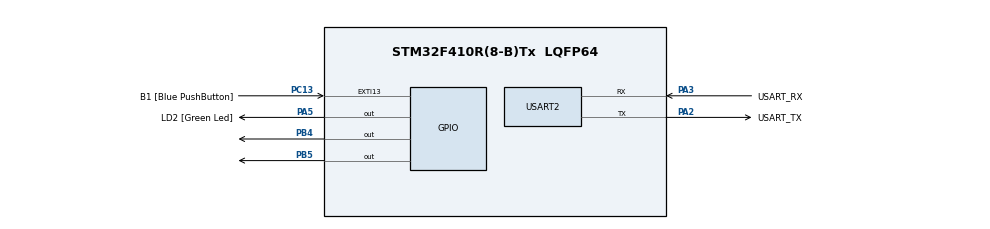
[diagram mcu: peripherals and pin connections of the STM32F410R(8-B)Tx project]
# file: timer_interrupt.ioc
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Dma.Request0=USART2_RX
Dma.Request1=USART2_TX
Dma.USART2_RX.0.Direction=DMA_PERIPH_TO_MEMORY
Dma.USART2_RX.0.FIFOMode=DMA_FIFOMODE_DISABLE
Dma.USART2_RX.0.Instance=DMA1_Stream5
Dma.USART2_RX.0.MemDataAlignment=DMA_MDATAALIGN_BYTE
Dma.USART2_RX.0.MemInc=DMA_MINC_ENABLE
Dma.USART2_RX.0.Mode=DMA_NORMAL
Dma.USART2_RX.0.PeriphDataAlignment=DMA_PDATAALIGN_BYTE
Dma.USART2_RX.0.PeriphInc=DMA_PINC_DISABLE
Dma.USART2_RX.0.Priority=DMA_PRIORITY_HIGH
Dma.USART2_TX.1.Direction=DMA_MEMORY_TO_PERIPH
Dma.USART2_TX.1.FIFOMode=DMA_FIFOMODE_DISABLE
Dma.USART2_TX.1.Instance=DMA1_Stream6
Dma.USART2_TX.1.MemDataAlignment=DMA_MDATAALIGN_BYTE
Dma.USART2_TX.1.MemInc=DMA_MINC_ENABLE
Dma.USART2_TX.1.Mode=DMA_NORMAL
Dma.USART2_TX.1.PeriphDataAlignment=DMA_PDATAALIGN_BYTE
Dma.USART2_TX.1.PeriphInc=DMA_PINC_DISABLE
Dma.USART2_TX.1.Priority=DMA_PRIORITY_HIGH
FREERTOS.Tasks01=defaultTask,0,128,StartDefaultTask,Default,NULL,Dynamic,NULL,NULL
FREERTOS.configUSE_NEWLIB_REENTRANT=1
Mcu.Family=STM32F4
Mcu.Name=STM32F410R(8-B)Tx
Mcu.Package=LQFP64
NVIC.DMA1_Stream5_IRQn=true\:5\:0\:false\:false\:true\:true\:false\:true\:true
NVIC.DMA1_Stream6_IRQn=true\:5\:0\:false\:false\:true\:true\:false\:true\:true
NVIC.PriorityGroup=NVIC_PRIORITYGROUP_4
NVIC.TIM1_BRK_TIM9_IRQn=true\:5\:0\:true\:false\:true\:true\:false\:true\:true
NVIC.TIM1_UP_IRQn=true\:5\:0\:false\:false\:true\:true\:true\:true\:true
NVIC.TimeBase=TIM1_BRK_TIM9_IRQn
NVIC.TimeBaseIP=TIM9
NVIC.USART2_IRQn=true\:5\:0\:false\:false\:true\:true\:true\:true\:true
PA13.GPIO_Label=TMS
PA13.Mode=Serial_Wire
PA13.Signal=SYS_JTMS-SWDIO
PA14.GPIO_Label=TCK
PA14.Mode=Serial_Wire
PA14.Signal=SYS_JTCK-SWCLK
PA2.GPIO_Label=USART_TX
PA2.Mode=Asynchronous
PA2.Signal=USART2_TX
PA3.GPIO_Label=USART_RX
PA3.Mode=Asynchronous
PA3.Signal=USART2_RX
PA5.GPIO_Label=LD2 [Green Led]
PA5.Signal=GPIO_Output
PB3.GPIO_Label=SWO
PB3.Signal=SYS_JTDO-SWO
PB4.Signal=GPIO_Output
PB5.Signal=GPIO_Output
PC13-ANTI_TAMP.GPIO_Label=B1 [Blue PushButton]
PC13-ANTI_TAMP.GPIO_ModeDefaultEXTI=GPIO_MODE_IT_FALLING
PC13-ANTI_TAMP.Signal=GPXTI13
PC14-OSC32_IN.Mode=LSE-External-Oscillator
PC14-OSC32_IN.Signal=RCC_OSC32_IN
PC15-OSC32_OUT.Mode=LSE-External-Oscillator
PC15-OSC32_OUT.Signal=RCC_OSC32_OUT
PH0\ -\ OSC_IN.Mode=HSE-External-Clock-Source
PH0\ -\ OSC_IN.Signal=RCC_OSC_IN
PH1\ -\ OSC_OUT.Mode=HSE-External-Clock-Source
PH1\ -\ OSC_OUT.Signal=RCC_OSC_OUT
ProjectManager.HeapSize=0x200
ProjectManager.StackSize=0x400
ProjectManager.TargetToolchain=STM32CubeIDE
RCC.48MHZClocksFreq_Value=84000000
RCC.AHBFreq_Value=84000000
RCC.APB1CLKDivider=RCC_HCLK_DIV2
RCC.APB1Freq_Value=42000000
RCC.APB1TimFreq_Value=84000000
RCC.APB2Freq_Value=84000000
RCC.APB2TimFreq_Value=84000000
RCC.CortexFreq_Value=84000000
RCC.FLatency-AdvancedSettings=FLASH_LATENCY_2
RCC.HCLKFreq_Value=84000000
RCC.HSE_VALUE=8000000
RCC.HSI_VALUE=16000000
RCC.PLLN=336
RCC.PLLP=RCC_PLLP_DIV4
RCC.SYSCLKFreq_VALUE=84000000
RCC.SYSCLKSource=RCC_SYSCLKSOURCE_PLLCLK
RCC.VCOOutputFreq_Value=336000000
USART2.VirtualMode=VM_ASYNC
VP_FATFS_VS_Generic.Mode=User_defined
VP_FREERTOS_VS_CMSIS_V1.Mode=CMSIS_V1
VP_SYS_VS_tim9.Mode=TIM9
VP_TIM1_VS_ClockSourceINT.Mode=Internal
board=NUCLEO-F410RB

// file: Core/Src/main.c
/* USER CODE BEGIN Header */
/**
  ******************************************************************************
  * @file           : main.c
  * @brief          : Main program body
  ******************************************************************************
  * @attention
  *
  * Copyright (c) 2024 STMicroelectronics.
  * All rights reserved.
  *
  * This software is licensed under terms that can be found in the LICENSE file
  * in the root directory of this software component.
  * If no LICENSE file comes with this software, it is provided AS-IS.
  *
  ******************************************************************************
  */
/* USER CODE END Header */
#include "main.h"
#include "string.h"
#include "freeRTOS.h"
#include "task.h"
#include <semphr.h>
#include <SEGGER_SYSVIEW.h>
#include <stm32f4xx_hal.h>
#include <stm32f4xx_it.h>
#include "fatfs.h"
#include "usart.h"
#include <timer.h>

/* USER CODE BEGIN Includes */

#define STACK_SIZE 128
void GreenTaskA( void * argument);
void BlueTaskB( void* argument );
void UartTaskC( void* argument );
void vHandlingTaskTimer (void* argument);
/* USER CODE END Includes */

/* USER CODE BEGIN PTD */
// Create storage for a pointer to a semaphore

SemaphoreHandle_t semPtr = NULL;

/* USER CODE END PTD */

TIM_HandleTypeDef htim1;

osThreadId defaultTaskHandle;

void SystemClock_Config(void);
static void MX_GPIO_Init(void);
static void MX_DMA_Init(void);
void MX_USART2_UART_Init(void);
static void MX_TIM1_Init(void);

int main(void)
{
  /* USER CODE BEGIN 1 */
	BaseType_t status;
  /* USER CODE END 1 */

  /* MCU Configuration--------------------------------------------------------*/

  /* Reset of all peripherals, Initializes the Flash interface and the Systick. */
  HAL_Init();

  /* Configure the system clock */
  SystemClock_Config();

  /* Initialize all configured peripherals */
  MX_GPIO_Init();
  MX_DMA_Init();
  MX_USART2_UART_Init();
  MX_FATFS_Init();
  MX_TIM1_Init();
  init_struct_timers();
  /* USER CODE BEGIN 2 */

  /* Init scheduler */
    SEGGER_SYSVIEW_Conf();

     		HAL_NVIC_SetPriorityGrouping(NVIC_PRIORITYGROUP_4);	//ensure proper priority grouping for freeRTOS

     		// Create a semaphore using the FreeRTOS Heap
     		semPtr = xSemaphoreCreateBinary();
     	    // Ensure the pointer is valid (semaphore created successfully)
     		assert_param(semPtr != NULL);

     		// Create TaskA as a higher priority than TaskB.  In this example, this isn't strictly necessary since the tasks
     		// spend nearly all of their time blocked

     		status=xTaskCreate(GreenTaskA, "GreenTaskA", STACK_SIZE, NULL, tskIDLE_PRIORITY + 2, NULL);
     		assert_param(status == pdPASS);
     		//xTaskCreateStatic(GreenTaskA, "GreenTaskA", STACK_SIZE, NULL, tskIDLE_PRIORITY + 2, GreenTaskStack, &GreenTaskTCB);
     		// Using an assert to ensure proper task creation
     		//xTaskCreateStatic(BlueTaskB, "BlueTaskB", STACK_SIZE, NULL, tskIDLE_PRIORITY + 2, BlueTaskStack, &BlueTaskTCB);
     		status=xTaskCreate(BlueTaskB, "BlueTaskB", STACK_SIZE, NULL, tskIDLE_PRIORITY + 2, NULL);
     		assert_param( status == pdPASS);

     		status=xTaskCreate(UartTaskC, "UartTaskC", STACK_SIZE, NULL, tskIDLE_PRIORITY + 2, NULL);
     		assert_param( status == pdPASS);

     		status=xTaskCreate(vHandlingTaskTimer, "vHandlingTaskTimer", STACK_SIZE, NULL, tskIDLE_PRIORITY + 2, NULL);
     		     		assert_param( status == pdPASS);
     		// Start the scheduler - shouldn't return unless there's a problem

     		HAL_TIM_Base_Start_IT(&htim1);

     		vTaskStartScheduler();

     		// If you've wound up here, there is likely an issue with over-running the freeRTOS heap
     		while(1)
     		{
     		}

   }

   /**
    * GreenTaskA periodically 'gives' semaphorePtr
    * NOTES:
    * - This semaphore isn't "given" to any task specifically
    * - Giving the semaphore doesn't prevent GreenTaskA from continuing to run.
    * - Note the green LED continues to blink at all times
    */
   void GreenTaskA( void* argument )
   {
   	uint_fast8_t count = 0;
   	while(1)
   	{
   		// Every 5 times through the loop, give the semaphore
   		if(++count >= 5)
   		{
   			count = 0;
   			SEGGER_SYSVIEW_PrintfHost("GreenTaskA gives semPtr");
   			xSemaphoreGive(semPtr);
   		}
   		HAL_GPIO_WritePin(GPIOA, GPIO_PIN_5, GPIO_PIN_SET);
   		vTaskDelay(100/portTICK_PERIOD_MS);
   		//vTaskDelay(pdMS_TO_TICKS(100));
   		HAL_GPIO_WritePin(GPIOA, GPIO_PIN_5, GPIO_PIN_RESET);
   		vTaskDelay(100/portTICK_PERIOD_MS);
   		//vTaskDelay(pdMS_TO_TICKS(100));
   	}
   }

   /**
    * BlueTaskB waits to receive semPtr, then triple-blinks the blue LED
    */
   void BlueTaskB( void* argument )
   {
   	while(1)
   	{
   		// 'take' the semaphore with no timeout.
   	    // * In our system, FreeRTOSConfig.h specifies "#define INCLUDE_vTaskSuspend 1".
   	    // * So, in xSemaphoreTake, portMAX_DELAY specifies an indefinite wait.
   		SEGGER_SYSVIEW_PrintfHost("BlueTaskB attempts to take semPtr");
   		if(xSemaphoreTake(semPtr, 500/portTICK_PERIOD_MS) == pdPASS)
   		{
   			SEGGER_SYSVIEW_PrintfHost("BlueTaskB received semPtr");
   			// Triple-blink the Blue LED
   			for(uint_fast8_t i = 0; i < 3; i++)
   			{
   				HAL_GPIO_WritePin(GPIOB, GPIO_PIN_5, GPIO_PIN_SET);
   				//vTaskDelay(pdMS_TO_TICKS(50));
   				vTaskDelay(50/portTICK_PERIOD_MS);
   				HAL_GPIO_WritePin(GPIOB, GPIO_PIN_5, GPIO_PIN_RESET);
   				vTaskDelay(50/portTICK_PERIOD_MS);
   				//vTaskDelay(pdMS_TO_TICKS(500));
   			}
   		}
   		else
   		{
   		//	This is the code that would be executed if we timed-out waiting for
   		//	the semaphore to be given.
   			HAL_GPIO_WritePin(GPIOB, GPIO_PIN_6, GPIO_PIN_SET);
   			vTaskDelay(25/ portTICK_PERIOD_MS);
   			//vTaskDelay(pdMS_TO_TICKS(500));
   			 HAL_GPIO_WritePin(GPIOB, GPIO_PIN_6, GPIO_PIN_RESET);

   		}
   	}
   }

   void UartTaskC( void* argument )
      {
      	while(1)
      	{
      		uint8_t temp_buffer[64];
      	//	uint16_t temp_buffer[sizeof(send_esp)];

			size_t read_bytes;
			SEGGER_SYSVIEW_PrintfHost("UartTaskC started");
			read_bytes =get_rx_data(temp_buffer, sizeof(temp_buffer), 100);

			//read_bytes =get_rx_data("data to print", sizeof("data to print"), 100);
			SEGGER_SYSVIEW_PrintfHost("read");
			put_tx_data_with_wait(temp_buffer,read_bytes);

			//put_tx_data_with_wait("data to print",read_bytes);
			SEGGER_SYSVIEW_PrintfHost("write");
      	}
      }

   void vHandlingTaskTimer( void *pvParameters )
   {
   uint32_t ulInterruptStatus;
   SEGGER_SYSVIEW_PrintfHost("vHandlingTaskTimer notification call");
   	   while(1)
       {
    	   /* Block indefinitely (without a timeout, so no need to check the function's
    	           return value) to wait for a notification.  NOTE!  Real applications
    	           should not block indefinitely, but instead time out occasionally in order
    	           to handle error conditions that may prevent the interrupt from sending
    	           any more notifications. */
    	           xTaskNotifyWait( 0,                  /* Wait for 0th Notificaition */
    	                                   0,          /* Clear all bits on exit. */
    	                                   &ulInterruptStatus, /* Receives the notification value. */
    	                                   portMAX_DELAY );    /* Block indefinitely. */

    	          static uint8_t counter=0;
    	           if(counter==0){
    	        	   counter++;

    	        	  // SEGGER_SYSVIEW_PrintfHost(counter);
    	           }

       }

   }

   /*****************************************************************************/
   /*****************************************************************************/
   void HAL_TIM_PeriodElapsedCallback(TIM_HandleTypeDef *htim){
   //void HAL_TIM_TriggerCallback(TIM_HandleTypeDef *htim){

	   HAL_GPIO_WritePin(GPIOB, GPIO_PIN_6, GPIO_PIN_SET);

   	  if (htim->Instance == TIM9) {
   	    HAL_IncTick();
   	  }
   /*****************************************************************************/
   	if (htim->Instance==TIM1){ //check if the interrupt comes from TIM1

   		SEGGER_SYSVIEW_PrintfHost("Interrupt");
   		BaseType_t xHigherPriorityTaskWoken;
   		uint32_t ulStatusRegister;
   		BaseType_t xTaskNotifyFromISR;

   		timer.f_10ms[0]=1;
   				timer.f_10ms[1]=1;
   				timer.f_10ms[2]=1;
   				timer.f_10ms[3]=1;
   				timer.f_10ms[4]=1;
   				timer.f_10ms[5]=1;
   				timer.f_10ms[6]=1;
   				timer.f_10ms[7]=1;

   				timer.count[0]++;
   				timer.count[1]++;
   				timer.count[2]++;

   				 xTaskNotifyFromISR( vHandlingTaskTimer,
   				                               0,
											   eNoAction,
   				                               &xHigherPriorityTaskWoken );
   //				 The macro used to do this is dependent on the port and may be called
   //				     portEND_SWITCHING_ISR. */
   				     portYIELD_FROM_ISR( xHigherPriorityTaskWoken );

   		    // timer envent 100ms
   		    if(timer.count[0]>=10){
   		        timer.count[0]=0;
   				timer.f_100ms[0]=!timer.f_100ms[0];
   		        timer.f_100ms[1]=1;
   		        timer.f_100ms[2]=1;
   		        timer.f_100ms[3]=1;
   		        timer.f_100ms[4]=1;
   		        timer.f_100ms[5]=1;

   						 //PutsU1("\n Test 100ms\0");
   		    }

   		    // timer envent 500ms
   		    if(timer.count[1]>=50){
   		         timer.count[1]=0;
   		         timer.f_500ms[0]=!timer.f_500ms[0];
   		         timer.f_500ms[1]=1;
   		         timer.f_500ms[2]=1;
   		         timer.f_500ms[3]=1;
   		         timer.f_500ms[4]=1;
   		         timer.f_500ms[5]=1;
   						 //PutsU1("\n Test 500ms\0");
   		    }

   		    // timer envent 1000ms
   		    if(timer.count[2]>=100){
   		         timer.count[2]=0;
   		         timer.f_1000ms[0]=!timer.f_1000ms[0];
   		         timer.f_1000ms[1]=1;
   		         timer.f_1000ms[2]=1;
   		         timer.f_1000ms[3]=1;
   		         timer.f_1000ms[4]=1;
   		         timer.f_1000ms[5]=1;
   						// PutsU1("\n Test 1000ms\0");

   		   		}

   		}

   }

static void MX_TIM1_Init(void)
{

  TIM_ClockConfigTypeDef sClockSourceConfig = {0};
  TIM_MasterConfigTypeDef sMasterConfig = {0};

  htim1.Instance = TIM1;
  htim1.Init.Prescaler = 200;
  htim1.Init.CounterMode = TIM_COUNTERMODE_UP;
  htim1.Init.Period = 3599;
  htim1.Init.ClockDivision = TIM_CLOCKDIVISION_DIV1;
  htim1.Init.RepetitionCounter = 0;
  htim1.Init.AutoReloadPreload = TIM_AUTORELOAD_PRELOAD_DISABLE;
  if (HAL_TIM_Base_Init(&htim1) != HAL_OK)
  {
    Error_Handler();
  }
  sClockSourceConfig.ClockSource = TIM_CLOCKSOURCE_INTERNAL;
  if (HAL_TIM_ConfigClockSource(&htim1, &sClockSourceConfig) != HAL_OK)
  {
    Error_Handler();
  }
  sMasterConfig.MasterOutputTrigger = TIM_TRGO_RESET;
  sMasterConfig.MasterSlaveMode = TIM_MASTERSLAVEMODE_DISABLE;
  if (HAL_TIMEx_MasterConfigSynchronization(&htim1, &sMasterConfig) != HAL_OK)
  {
    Error_Handler();
  }

}

void Error_Handler(void)
{
  __disable_irq();
  while (1)
  {
  }
}
void SystemClock_Config(void)
{
  RCC_OscInitTypeDef RCC_OscInitStruct = {0};
  RCC_ClkInitTypeDef RCC_ClkInitStruct = {0};

  /** Configure the main internal regulator output voltage
  */
  __HAL_RCC_PWR_CLK_ENABLE();
  __HAL_PWR_VOLTAGESCALING_CONFIG(PWR_REGULATOR_VOLTAGE_SCALE1);

  /** Initializes the RCC Oscillators according to the specified parameters
  * in the RCC_OscInitTypeDef structure.
  */
  RCC_OscInitStruct.OscillatorType = RCC_OSCILLATORTYPE_HSE;
  RCC_OscInitStruct.HSEState = RCC_HSE_BYPASS;
  RCC_OscInitStruct.PLL.PLLState = RCC_PLL_ON;
  RCC_OscInitStruct.PLL.PLLSource = RCC_PLLSOURCE_HSE;
  RCC_OscInitStruct.PLL.PLLM = 4;
  RCC_OscInitStruct.PLL.PLLN = 72;
  RCC_OscInitStruct.PLL.PLLP = RCC_PLLP_DIV2;
  RCC_OscInitStruct.PLL.PLLQ = 4;
  RCC_OscInitStruct.PLL.PLLR = 2;
  if (HAL_RCC_OscConfig(&RCC_OscInitStruct) != HAL_OK)
  {
    Error_Handler();
  }

  /** Initializes the CPU, AHB and APB buses clocks
  */
  RCC_ClkInitStruct.ClockType = RCC_CLOCKTYPE_HCLK|RCC_CLOCKTYPE_SYSCLK
                              |RCC_CLOCKTYPE_PCLK1|RCC_CLOCKTYPE_PCLK2;
  RCC_ClkInitStruct.SYSCLKSource = RCC_SYSCLKSOURCE_PLLCLK;
  RCC_ClkInitStruct.AHBCLKDivider = RCC_SYSCLK_DIV1;
  RCC_ClkInitStruct.APB1CLKDivider = RCC_HCLK_DIV2;
  RCC_ClkInitStruct.APB2CLKDivider = RCC_HCLK_DIV1;

  if (HAL_RCC_ClockConfig(&RCC_ClkInitStruct, FLASH_LATENCY_2) != HAL_OK)
  {
    Error_Handler();
  }
}

static void MX_GPIO_Init(void)
{
  GPIO_InitTypeDef GPIO_InitStruct = {0};

  /* GPIO Ports Clock Enable */
  __HAL_RCC_GPIOC_CLK_ENABLE();
  __HAL_RCC_GPIOH_CLK_ENABLE();
  __HAL_RCC_GPIOA_CLK_ENABLE();
  __HAL_RCC_GPIOB_CLK_ENABLE();

  /*Configure GPIO pin Output Level */
  HAL_GPIO_WritePin(LD2_GPIO_Port, LD2_Pin, GPIO_PIN_RESET);

  /*Configure GPIO pin Output Level */
  HAL_GPIO_WritePin(GPIOB, GPIO_PIN_4|GPIO_PIN_5|GPIO_PIN_6, GPIO_PIN_RESET);

  /*Configure GPIO pin : B1_Pin */
  GPIO_InitStruct.Pin = B1_Pin;
  GPIO_InitStruct.Mode = GPIO_MODE_IT_FALLING;
  GPIO_InitStruct.Pull = GPIO_NOPULL;
  HAL_GPIO_Init(B1_GPIO_Port, &GPIO_InitStruct);

  /*Configure GPIO pin : LD2_Pin */
  GPIO_InitStruct.Pin = LD2_Pin;
  GPIO_InitStruct.Mode = GPIO_MODE_OUTPUT_PP;
  GPIO_InitStruct.Pull = GPIO_NOPULL;
  GPIO_InitStruct.Speed = GPIO_SPEED_FREQ_LOW;
  HAL_GPIO_Init(LD2_GPIO_Port, &GPIO_InitStruct);

  /*Configure GPIO pins : PB4 PB5 PB6 */
  GPIO_InitStruct.Pin = GPIO_PIN_4|GPIO_PIN_5|GPIO_PIN_6;
  GPIO_InitStruct.Mode = GPIO_MODE_OUTPUT_PP;
  GPIO_InitStruct.Pull = GPIO_NOPULL;
  GPIO_InitStruct.Speed = GPIO_SPEED_FREQ_LOW;
  HAL_GPIO_Init(GPIOB, &GPIO_InitStruct);

}
